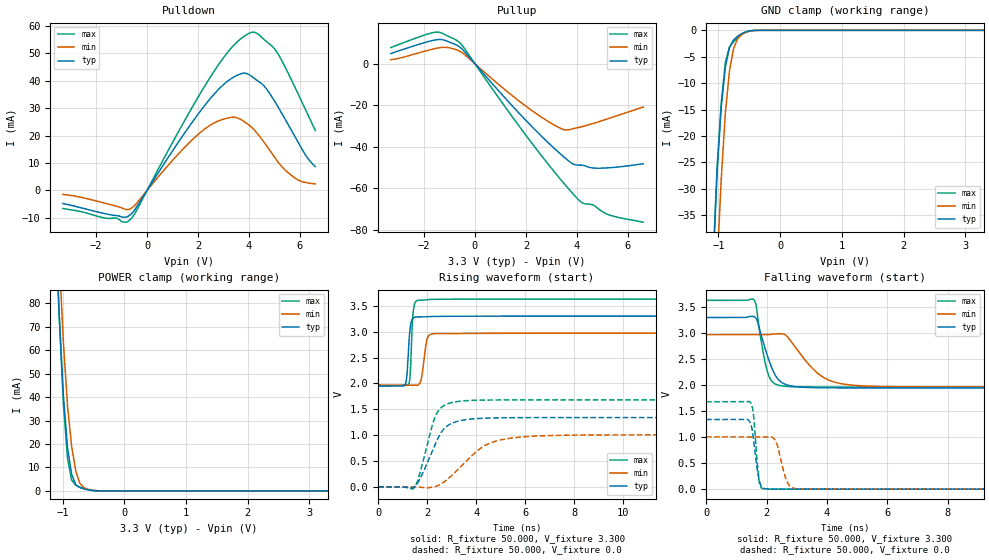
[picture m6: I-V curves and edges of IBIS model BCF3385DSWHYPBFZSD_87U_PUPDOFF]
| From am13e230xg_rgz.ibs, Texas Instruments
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|   Model BCF3385DSWHYPBFZSD_87U_PUPDOFF
[Model] BCF3385DSWHYPBFZSD_87U_PUPDOFF
Model_type I/O
Polarity   Non-Inverting
Enable   Active-Low
Vinl =  0.990V
Vinh =  2.310V
Vmeas =  1.650V
C_comp   0.589pF   0.544pF   0.642pF
[Model Spec]
Vinh   2.310V   2.079V   2.541V
Vinl   0.990V   0.891V   1.089V
Vmeas   1.650V   1.485V   1.815V
[Temperature Range]   25.000   0.155k   -40.000
[Voltage Range]   3.300V   2.970V   3.630V
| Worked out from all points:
|   slope of the pulldown table from 0 to 0.495 V, typ, clamps not added: 68.5 ohm
|   slope of the pullup table from 0 to 0.495 V, typ, clamps not added: 70.5 ohm
|   GND clamp passes 1 mA (typ) near -0.67 V on its own axis
|   POWER clamp passes 1 mA (typ) near -0.67 V on its own axis
|   rising waveform, R_fixture 50.000, V_fixture 3.300: 20-80 % time 111ps typ, 164ps min, 92.6ps max; typ from 1.95 V to 3.3 V
|   rising waveform, R_fixture 50.000, V_fixture 0.0: 20-80 % time 780ps typ, 1.42ns min, 574ps max; typ from 0 V to 1.34 V
|   falling waveform, R_fixture 50.000, V_fixture 3.300: 20-80 % time 475ps typ, 936ps min, 302ps max; typ from 3.3 V to 1.95 V
|   falling waveform, R_fixture 50.000, V_fixture 0.0: 20-80 % time 180ps typ, 263ps min, 136ps max; typ from 1.34 V to 0 V
[Pulldown]
|Voltage   I(typ)   I(min)   I(max)
-3.3V     -4.737mA   -1.434mA   -6.536mA
-700mV    -9.139mA   -6.85mA    -10.9mA
-400mV    -5.896mA   -4.56mA    -7.102mA
1.4V      19.9mA     14.98mA    24.18mA
2.4V      32.52mA    23.27mA    40.03mA
3.4V      41.23mA    26.67mA    52.8mA
3.8V      42.7mA     25.1mA     56.03mA
4.1V      41.55mA    23.03mA    57.55mA
4.6V      37.91mA    17.42mA    54.82mA
5.1V      30.98mA    10.84mA    50.25mA
5.9V      17.99mA    3.944mA    35.63mA
6.6V      8.679mA    2.398mA    21.82mA
[Pullup]
|Voltage   I(typ)   I(min)   I(max)
-3.3V     4.905mA    1.948mA    7.774mA
-1.5V     11.57mA    7.47mA     15.24mA
-1.1V     10.9mA     7.867mA    13.54mA
-700mV    8.862mA    6.586mA    11.11mA
-400mV    5.722mA    4.387mA    7.145mA
2V        -27.28mA   -20.44mA   -34.45mA
3.5V      -44.99mA   -31.76mA   -57.74mA
3.9V      -48.53mA   -31.12mA   -63.36mA
4.2V      -48.82mA   -30.28mA   -66.92mA
4.6V      -50.15mA   -28.88mA   -67.85mA
5.3V      -50.04mA   -26.14mA   -72.92mA
6.6V      -48.15mA   -20.84mA   -76.29mA
[GND_clamp]
|Voltage   I(typ)   I(min)   I(max)
-3.3V     -1.005A    -882.7mA   -1.271A
-1.089V   -45.09mA   -63.71mA   -44.08mA
-1.022V   -26.78mA   -44.61mA   -25.91mA
-955mV    -14.5mA    -28.18mA   -13.82mA
-888mV    -7.031mA   -15.65mA   -6.009mA
-821mV    -3.19mA    -7.63mA    -3.172mA
-754mV    -1.786mA   -3.39mA    -2.152mA
-687mV    -1.097mA   -1.538mA   -1.4mA
-620mV    -601.8uA   -747.5uA   -783uA
-486mV    -70.11uA   -129.6uA   -99.51uA
-352mV    -1.527uA   -8.942uA   -1.719uA
3.3V      0A         0A         0A
[POWER_clamp]
|Voltage   I(typ)   I(min)   I(max)
-3.3V     1.773A     2.006A     1.904A
-1.122V   114.9mA    143mA      120.2mA
-1.055V   74.58mA    99.93mA    75.02mA
-988mV    40.95mA    63.52mA    37.26mA
-921mV    18.55mA    36.46mA    14.03mA
-854mV    7.114mA    18.98mA    4.661mA
-787mV    2.625mA    8.513mA    2.398mA
-720mV    1.421mA    3.259mA    1.613mA
-653mV    867.2uA    1.357mA    992.7uA
-586mV    464.5uA    678uA      496.8uA
-385mV    10.92uA    45.23uA    6.451uA
3.3V      0A         0A         0A
[Ramp]
| variable   typ   min   max
dV/dt_r   0.803/0.780n   0.603/1.419n   1.008/0.574n
dV/dt_f   0.812/0.475n   0.603/0.935n   1.000/0.302n
R_load = 50.000
[Rising Waveform]
R_fixture= 50.000
V_fixture= 3.300
V_fixture_min= 2.970
V_fixture_max= 3.630
|time   V(typ)   V(min)   V(max)
0s        1.947V     1.966V     1.964V
1.087ns   1.962V     1.966V     1.964V
1.167ns   2.122V     1.966V     1.963V
1.248ns   2.717V     1.966V     1.983V
1.313ns   3.1V       1.966V     2.22V
1.435ns   3.265V     1.965V     3.408V
1.639ns   3.286V     1.972V     3.607V
1.996ns   3.289V     2.856V     3.619V
2.249ns   3.294V     2.96V      3.624V
25ns      3.3V       2.97V      3.63V
[Rising Waveform]
R_fixture= 50.000
V_fixture= 0.0
V_fixture_min= 0.0
V_fixture_max= 0.0
|time   V(typ)   V(min)   V(max)
0s        1.137uV    1.018uV    1.022uV
1.478ns   2.284mV    647.5uV    -15.27mV
1.654ns   108.4mV    -3.141mV   182.9mV
2.192ns   675mV      -6.428mV   1.157V
2.381ns   880mV      12.32mV    1.409V
2.733ns   1.143V     110mV      1.583V
3.232ns   1.266V     323.6mV    1.649V
4.461ns   1.329V     824.1mV    1.678V
6.111ns   1.338V     973.3mV    1.681V
25ns      1.339V     1.006V     1.681V
[Falling Waveform]
R_fixture= 50.000
V_fixture= 3.300
V_fixture_min= 2.970
V_fixture_max= 3.630
|time   V(typ)   V(min)   V(max)
0s        3.3V       2.97V      3.63V
1.583ns   3.319V     2.97V      3.641V
1.656ns   3.281V     2.97V      3.528V
1.872ns   2.861V     2.97V      2.684V
2.055ns   2.518V     2.97V      2.214V
2.304ns   2.178V     2.986V     2.018V
2.575ns   2.027V     2.979V     1.981V
3.807ns   1.95V      2.179V     1.964V
4.977ns   1.947V     1.993V     1.964V
25ns      1.947V     1.966V     1.964V
[Falling Waveform]
R_fixture= 50.000
V_fixture= 0.0
V_fixture_min= 0.0
V_fixture_max= 0.0
|time   V(typ)   V(min)   V(max)
0s        1.339V     1.006V     1.681V
1.475ns   1.255V     1.006V     1.661V
1.569ns   963.2mV    1.006V     1.438V
1.692ns   384.8mV    1.005V     516.5mV
1.761ns   166mV      1.005V     133.3mV
1.917ns   14.71mV    1.006V     7.764mV
2.278ns   1.953mV    946.7mV    1.511mV
2.687ns   764.9uV    137.6mV    435.8uV
3.027ns   355.8uV    7.326mV    146.7uV
25ns      334.8nV    605.8nV    344.6nV
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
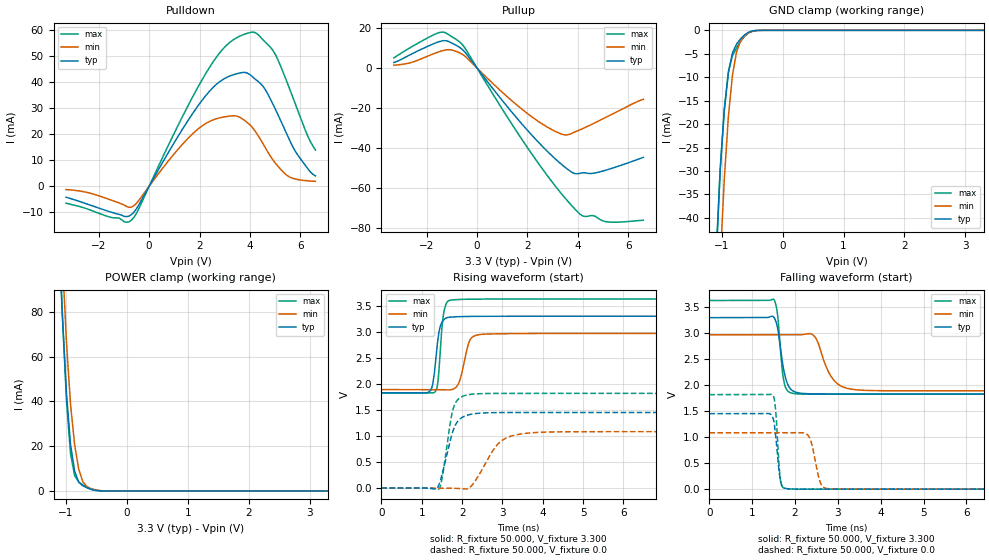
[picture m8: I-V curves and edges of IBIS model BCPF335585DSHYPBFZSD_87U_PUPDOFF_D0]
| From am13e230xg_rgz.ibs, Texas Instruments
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|   Model BCPF335585DSHYPBFZSD_87U_PUPDOFF_D0
[Model] BCPF335585DSHYPBFZSD_87U_PUPDOFF_D0
Model_type I/O
Polarity   Non-Inverting
Enable   Active-Low
Vinl =  0.990V
Vinh =  2.310V
Vmeas =  1.650V
C_comp   0.811pF   0.754pF   0.883pF
[Model Spec]
Vinh   2.310V   2.079V   2.541V
Vinl   0.990V   0.891V   1.089V
Vmeas   1.650V   1.485V   1.815V
[Temperature Range]   25.000   0.155k   -40.000
[Voltage Range]   3.300V   2.970V   3.630V
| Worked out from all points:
|   slope of the pulldown table from 0 to 0.495 V, typ, clamps not added: 58.3 ohm
|   slope of the pullup table from 0 to 0.495 V, typ, clamps not added: 60.6 ohm
|   GND clamp passes 1 mA (typ) near -0.62 V on its own axis
|   POWER clamp passes 1 mA (typ) near -0.61 V on its own axis
|   rising waveform, R_fixture 50.000, V_fixture 3.300: 20-80 % time 129ps typ, 192ps min, 108ps max; typ from 1.83 V to 3.3 V
|   rising waveform, R_fixture 50.000, V_fixture 0.0: 20-80 % time 292ps typ, 524ps min, 215ps max; typ from 0 V to 1.45 V
|   falling waveform, R_fixture 50.000, V_fixture 3.300: 20-80 % time 170ps typ, 329ps min, 114ps max; typ from 3.3 V to 1.83 V
|   falling waveform, R_fixture 50.000, V_fixture 0.0: 20-80 % time 104ps typ, 166ps min, 81.1ps max; typ from 1.45 V to 0 V
[Pulldown]
|Voltage   I(typ)   I(min)   I(max)
-3.3V     -4.194mA   -1.269mA   -6.487mA
-1V       -11.51mA   -7.186mA   -13.57mA
-700mV    -10.84mA   -8mA       -12.94mA
1.2V      20mA       14.78mA    24.38mA
2.1V      32.98mA    23.15mA    40.84mA
3V        41.37mA    26.65mA    53.41mA
3.5V      43.24mA    26.86mA    57.13mA
4V        42.83mA    23.59mA    58.98mA
4.5V      38.6mA     16.64mA    56.38mA
5V        29.76mA    8.974mA    50.75mA
5.8V      13.44mA    2.784mA    31.63mA
6.6V      3.976mA    1.886mA    13.89mA
[Pullup]
|Voltage   I(typ)   I(min)   I(max)
-3.3V     2.806mA    1.428mA    5.139mA
-1.5V     13.25mA    8.216mA    17.8mA
-800mV    11.23mA    8.235mA    14.14mA
-500mV    8.247mA    6.145mA    10.41mA
1.1V      -17.8mA    -13.27mA   -22.58mA
2.3V      -35.4mA    -25.61mA   -45.39mA
3.3V      -47.75mA   -32.85mA   -62.26mA
3.8V      -52.56mA   -32.52mA   -69.6mA
4.2V      -52.52mA   -30.33mA   -74.24mA
4.6V      -52.8mA    -27.94mA   -74mA
5.1V      -51.26mA   -24.8mA    -77.03mA
6.6V      -44.79mA   -15.66mA   -76.33mA
[GND_clamp]
|Voltage   I(typ)   I(min)   I(max)
-3.3V     -1.05A     -924.7mA   -1.319A
-1.089V   -48.91mA   -69.18mA   -47.99mA
-1.022V   -29.79mA   -49.12mA   -29.48mA
-955mV    -16.94mA   -31.76mA   -17.01mA
-888mV    -9.058mA   -18.35mA   -8.783mA
-821mV    -4.809mA   -9.52mA    -5.378mA
-754mV    -2.93mA    -4.589mA   -3.691mA
-687mV    -1.795mA   -2.237mA   -2.338mA
-620mV    -951.1uA   -1.117mA   -1.252mA
-553mV    -382.8uA   -509uA     -513.2uA
-352mV    -2.13uA    -12.42uA   -2.39uA
3.3V      0A         0A         0A
[POWER_clamp]
|Voltage   I(typ)   I(min)   I(max)
-3.3V     1.851A     2.08A      1.997A
-1.122V   119.7mA    148.8mA    125.5mA
-1.055V   78.16mA    104.2mA    79.19mA
-988mV    43.66mA    66.59mA    40.55mA
-921mV    20.7mA     38.68mA    16.69mA
-854mV    8.846mA    20.65mA    6.818mA
-787mV    3.933mA    9.757mA    4.019mA
-720mV    2.311mA    4.145mA    2.698mA
-653mV    1.397mA    1.942mA    1.618mA
-519mV    286.9uA    510.4uA    258.6uA
-318mV    2.223uA    16.05uA    1.035uA
3.3V      0A         0A         0A
[Ramp]
| variable   typ   min   max
dV/dt_r   0.871/0.292n   0.650/0.525n   1.091/0.215n
dV/dt_f   0.882/0.171n   0.647/0.329n   1.082/0.113n
R_load = 50.000
[Rising Waveform]
R_fixture= 50.000
V_fixture= 3.300
V_fixture_min= 2.970
V_fixture_max= 3.630
|time   V(typ)   V(min)   V(max)
0s        1.831V     1.892V     1.826V
1.173ns   1.844V     1.892V     1.827V
1.341ns   2.413V     1.891V     1.858V
1.41ns    2.921V     1.891V     2.108V
1.544ns   3.231V     1.887V     3.361V
1.762ns   3.287V     1.896V     3.614V
1.935ns   3.292V     2.051V     3.622V
2.198ns   3.297V     2.847V     3.628V
2.528ns   3.299V     2.955V     3.63V
25ns      3.3V       2.97V      3.63V
[Rising Waveform]
R_fixture= 50.000
V_fixture= 0.0
V_fixture_min= 0.0
V_fixture_max= 0.0
|time   V(typ)   V(min)   V(max)
0s        792.2nV    899.6nV    725.3nV
1.349ns   -20.16mV   475.9uV    -12.44mV
1.436ns   86.28mV    674.3uV    -9.234mV
1.499ns   248.4mV    825.7uV    163.5mV
1.71ns    927mV      -1.008mV   1.272V
1.8ns     1.152V     -3.119mV   1.574V
2.266ns   1.424V     75.48mV    1.805V
2.952ns   1.451V     892.3mV    1.818V
3.822ns   1.452V     1.067V     1.819V
25ns      1.452V     1.084V     1.819V
[Falling Waveform]
R_fixture= 50.000
V_fixture= 3.300
V_fixture_min= 2.970
V_fixture_max= 3.630
|time   V(typ)   V(min)   V(max)
0s        3.3V       2.97V      3.63V
1.506ns   3.308V     2.97V      3.651V
1.589ns   3.119V     2.97V      3.384V
1.69ns    2.53V      2.97V      2.388V
1.751ns   2.236V     2.97V      2.031V
2.029ns   1.863V     2.969V     1.834V
2.429ns   1.833V     2.961V     1.826V
2.915ns   1.831V     2.087V     1.826V
3.543ns   1.831V     1.905V     1.826V
25ns      1.831V     1.892V     1.826V
[Falling Waveform]
R_fixture= 50.000
V_fixture= 0.0
V_fixture_min= 0.0
V_fixture_max= 0.0
|time   V(typ)   V(min)   V(max)
0s        1.452V     1.084V     1.819V
1.487ns   1.367V     1.084V     1.805V
1.545ns   1.06V      1.084V     1.551V
1.626ns   359.3mV    1.084V     458.8mV
1.662ns   154mV      1.084V     160.1mV
1.837ns   7.669mV    1.084V     5.675mV
2.308ns   211.7uV    1.03V      66.57uV
2.596ns   42.53uV    115.5mV    17.63uV
2.822ns   18.87uV    7.285mV    11.44uV
25ns      325.7nV    741.6nV    334.7nV
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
